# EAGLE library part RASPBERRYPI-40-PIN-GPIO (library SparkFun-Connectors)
Raspberry Pi GPIO Header 2x20 pin connector, as found on B, B+, A+ models. Both shrouded PTH and SMT versions available. SparkFun Products: GPIO Shrouded Header- PTH SparkFun Pi Wedge (Preassembled)

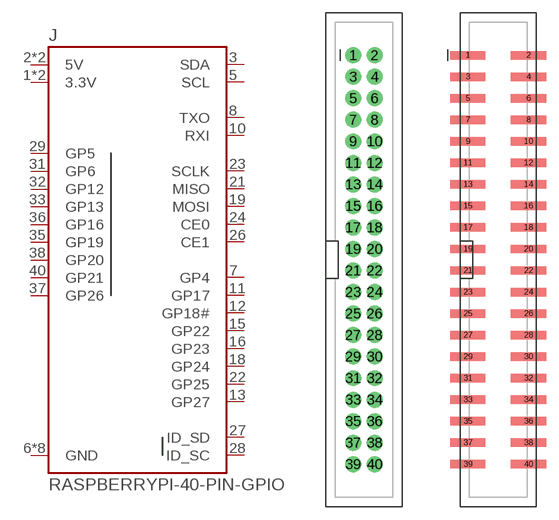
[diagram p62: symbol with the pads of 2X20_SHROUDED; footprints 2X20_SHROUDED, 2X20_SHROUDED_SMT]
Designator prefix J

## RASPBERRYPI-40-PIN-GPIO_PTH (PROD_ID: CONN-12263; SF_ID: PRT-13054)  [2X20_SHROUDED]
1  3.3V  pwr
2  5V  pwr
3  SDA
4  5V  pwr
5  SCL
6  GND  pwr
7  GP4
8  TXO  out
9  GND  pwr
10  RXI  in
11  GP17
12  GP18#
13  GP27
14  GND  pwr
15  GP22
16  GP23
17  3.3V  pwr
18  GP24
19  MOSI  out
20  GND  pwr
21  MISO  in
22  GP25
23  SCLK  out
24  CE0  out
25  GND  pwr
26  CE1  out
27  ID_SD
28  ID_SC
29  GP5
30  GND  pwr
31  GP6
32  GP12
33  GP13
34  GND  pwr
35  GP19
36  GP16
37  GP26
38  GP20
39  GND  pwr
40  GP21

## RASPBERRYPI-40-PIN-GPIO_SMT (PROD_ID: CONN-13143)  [2X20_SHROUDED_SMT]
Pads as for 2X20_SHROUDED

## RASPBERRYPI-40-PIN-GPIO_PTH_NO_SHROUD  [2X20]
Pads as for 2X20_SHROUDED

## RASPBERRYPI-40-PIN-GPIO_PTH_REFERENCE  [RASPBERRY_PI_HAT_40_PIN_PTH_WITH_REFERNCE]
Pads as for 2X20_SHROUDED

## RASPBERRYPI-40-PIN-GPIO_SMD_STACKABLE (PROD_ID: CONN-14914; PROD_ID_2: CONN-14915)  [RASPBERRY_PI_HAT_40_PIN_SMD_STACKABLE]
1  3.3V  pwr
1B  3.3V  pwr
2  5V  pwr
2B  5V  pwr
3  SDA
3B  SDA
4  5V  pwr
4B  5V  pwr
5  SCL
5B  SCL
6  GND  pwr
6B  GND  pwr
7  GP4
7B  GP4
8  TXO  out
8B  TXO  out
9  GND  pwr
9B  GND  pwr
10  RXI  in
10B  RXI  in
11  GP17
11B  GP17
12  GP18#
12B  GP18#
13  GP27
13B  GP27
14  GND  pwr
14B  GND  pwr
15  GP22
15B  GP22
16  GP23
16B  GP23
17  3.3V  pwr
17B  3.3V  pwr
18  GP24
18B  GP24
19  MOSI  out
19B  MOSI  out
20  GND  pwr
20B  GND  pwr
21  MISO  in
21B  MISO  in
22  GP25
22B  GP25
23  SCLK  out
23B  SCLK  out
24  CE0  out
24B  CE0  out
25  GND  pwr
25B  GND  pwr
26  CE1  out
26B  CE1  out
27  ID_SD
27B  ID_SD
28  ID_SC
28B  ID_SC
29  GP5
29B  GP5
30  GND  pwr
30B  GND  pwr
31  GP6
31B  GP6
32  GP12
32B  GP12
33  GP13
33B  GP13
34  GND  pwr
34B  GND  pwr
35  GP19
35B  GP19
36  GP16
36B  GP16
37  GP26
37B  GP26
38  GP20
38B  GP20
39  GND  pwr
39B  GND  pwr
40  GP21
40B  GP21

## RASPBERRYPI-40-PIN-GPIO_SMD_STACKABLE_NOHOLES (PROD_ID: CONN-14914; PROD_ID_2: CONN-14915)  [RASPBERRY_PI_HAT_40_PIN_SMD_STACKABLE_NOHOLES]
Pads as for RASPBERRY_PI_HAT_40_PIN_SMD_STACKABLE

## RASPBERRYPI-40-PIN-GPIO_SMD_STACK_NOHOLES_NOREF  [RASPBERRY_PI_HAT_40_PIN_SMD_STACKABLE_NOHOLES_NOREF]
Pads as for RASPBERRY_PI_HAT_40_PIN_SMD_STACKABLE

## Footprint 2X20_SHROUDED (pad centres in mm)
Plated Through Hole - 2x20 Shrouded Header Specifications: Pin count:40 Pin pitch:0.1" Datasheet referenced for footprint Example device(s): CONN_20x2
drill 1.016 pad 1.88: 1 -1.27,24.13; 2 1.27,24.13; 3 -1.27,21.59; 4 1.27,21.59; 5 -1.27,19.05; 6 1.27,19.05; 7 -1.27,16.51; 8 1.27,16.51; 9 -1.27,13.97; 10 1.27,13.97; 11 -1.27,11.43; 12 1.27,11.43; 13 -1.27,8.89; 14 1.27,8.89; 15 -1.27,6.35; 16 1.27,6.35; 17 -1.27,3.81; 18 1.27,3.81; 19 -1.27,1.27; 20 1.27,1.27; 21 -1.27,-1.27; 22 1.27,-1.27; 23 -1.27,-3.81; 24 1.27,-3.81; 25 -1.27,-6.35; 26 1.27,-6.35; 27 -1.27,-8.89; 28 1.27,-8.89; 29 -1.27,-11.43; 30 1.27,-11.43; 31 -1.27,-13.97; 32 1.27,-13.97; 33 -1.27,-16.51; 34 1.27,-16.51; 35 -1.27,-19.05; 36 1.27,-19.05; 37 -1.27,-21.59; 38 1.27,-21.59; 39 -1.27,-24.13; 40 1.27,-24.13

## Footprint 2X20_SHROUDED_SMT (pad centres in mm)
Surface Mount - 2x20 Shrouded Header Specifications: Pin count:40 Pin pitch:0.1" Datasheet referenced for footprint Example device(s): CONN_20x2
smd 4.14 x 0.991: 1 -3.569,24.13; 2 3.569,24.13; 3 -3.569,21.59; 4 3.569,21.59; 5 -3.569,19.05; 6 3.569,19.05; 7 -3.569,16.51; 8 3.569,16.51; 9 -3.569,13.97; 10 3.569,13.97; 11 -3.569,11.43; 12 3.569,11.43; 13 -3.569,8.89; 14 3.569,8.89; 15 -3.569,6.35; 16 3.569,6.35; 17 -3.569,3.81; 18 3.569,3.81; 19 -3.569,1.27; 20 3.569,1.27; 21 -3.569,-1.27; 22 3.569,-1.27; 23 -3.569,-3.81; 24 3.569,-3.81; 25 -3.569,-6.35; 26 3.569,-6.35; 27 -3.569,-8.89; 28 3.569,-8.89; 29 -3.569,-11.43; 30 3.569,-11.43; 31 -3.569,-13.97; 32 3.569,-13.97; 33 -3.569,-16.51; 34 3.569,-16.51; 35 -3.569,-19.05; 36 3.569,-19.05; 37 -3.569,-21.59; 38 3.569,-21.59; 39 -3.569,-24.13; 40 3.569,-24.13

## Footprint 2X20 (pad centres in mm)
Plated Through Hole - 2x20 Specifications: Pin count:40 Pin pitch:0.1" Example device(s): CONN_20x2
drill 1.016 pad 1.88: 1 0,0; 2 0,2.54; 3 2.54,0; 4 2.54,2.54; 5 5.08,0; 6 5.08,2.54; 7 7.62,0; 8 7.62,2.54; 9 10.16,0; 10 10.16,2.54; 11 12.7,0; 12 12.7,2.54; 13 15.24,0; 14 15.24,2.54; 15 17.78,0; 16 17.78,2.54; 17 20.32,0; 18 20.32,2.54; 19 22.86,0; 20 22.86,2.54; 21 25.4,0; 22 25.4,2.54; 23 27.94,0; 24 27.94,2.54; 25 30.48,0; 26 30.48,2.54; 27 33.02,0; 28 33.02,2.54; 29 35.56,0; 30 35.56,2.54; 31 38.1,0; 32 38.1,2.54; 33 40.64,0; 34 40.64,2.54; 35 43.18,0; 36 43.18,2.54; 37 45.72,0; 38 45.72,2.54; 39 48.26,0; 40 48.26,2.54

## Footprint RASPBERRY_PI_HAT_40_PIN_PTH_WITH_REFERNCE (pad centres in mm)
Plated Through Hole - 2x20 Specifications: Pin count:40 Pin pitch:0.1" Example device(s): CONN_20x2
drill 1.016 pad 1.88: 1 0,0; 2 0,2.54; 3 2.54,0; 4 2.54,2.54; 5 5.08,0; 6 5.08,2.54; 7 7.62,0; 8 7.62,2.54; 9 10.16,0; 10 10.16,2.54; 11 12.7,0; 12 12.7,2.54; 13 15.24,0; 14 15.24,2.54; 15 17.78,0; 16 17.78,2.54; 17 20.32,0; 18 20.32,2.54; 19 22.86,0; 20 22.86,2.54; 21 25.4,0; 22 25.4,2.54; 23 27.94,0; 24 27.94,2.54; 25 30.48,0; 26 30.48,2.54; 27 33.02,0; 28 33.02,2.54; 29 35.56,0; 30 35.56,2.54; 31 38.1,0; 32 38.1,2.54; 33 40.64,0; 34 40.64,2.54; 35 43.18,0; 36 43.18,2.54; 37 45.72,0; 38 45.72,2.54; 39 48.26,0; 40 48.26,2.54
hole 2.75 at -4.87,-47.727
hole 2.75 at 53.13,-47.727
hole 2.75 at 53.13,1.273
hole 2.75 at -4.87,1.273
